VERSION 5.7 ;
  NOWIREEXTENSIONATPIN ON ;
  DIVIDERCHAR "/" ;
  BUSBITCHARS "[]" ;
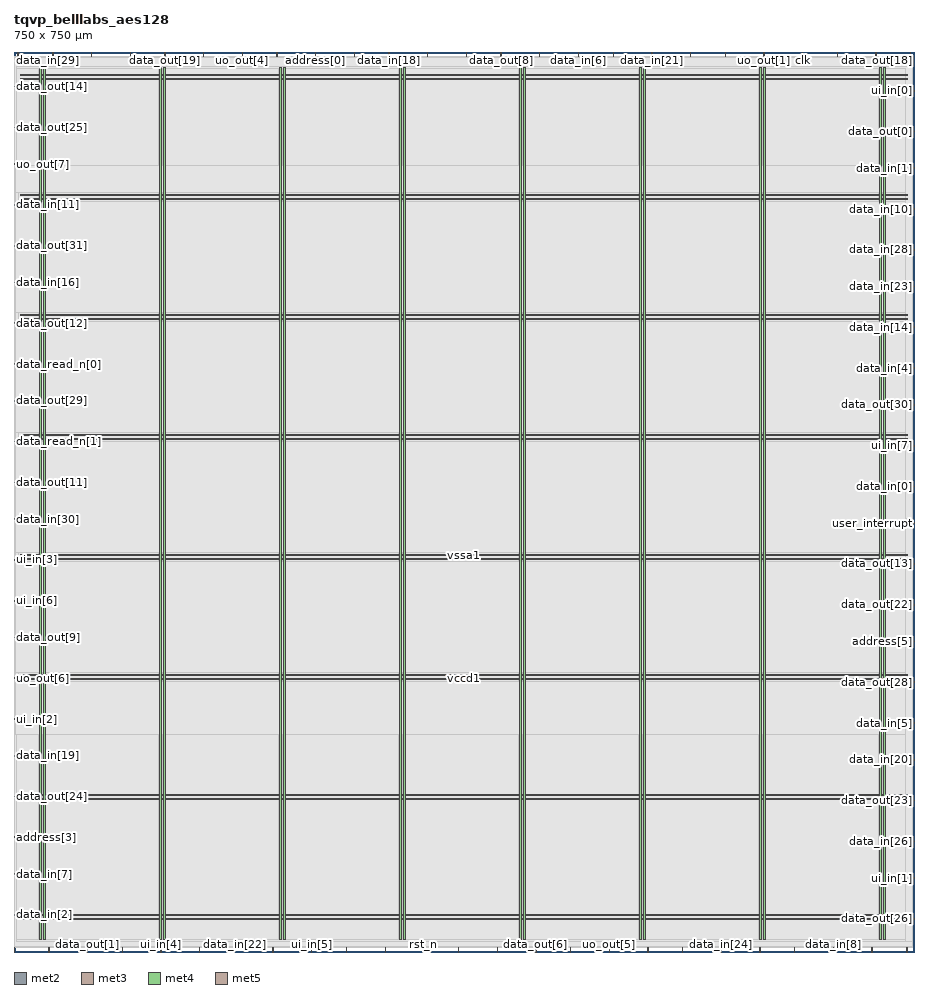
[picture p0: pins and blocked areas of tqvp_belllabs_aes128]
MACRO tqvp_belllabs_aes128
  CLASS BLOCK ;
  FOREIGN tqvp_belllabs_aes128 ;
  ORIGIN 0.000 0.000 ;
  SIZE 750.000 BY 750.000 ;
  PIN address[0]
    DIRECTION INPUT ;
    USE SIGNAL ;
    ANTENNAGATEAREA 0.647700 ;
    ANTENNADIFFAREA 0.434700 ;
    PORT
      LAYER met2 ;
        RECT 251.250 746.000 251.530 750.000 ;
    END
  END address[0]
  PIN address[1]
    DIRECTION INPUT ;
    USE SIGNAL ;
    ANTENNAGATEAREA 0.860700 ;
    ANTENNADIFFAREA 0.434700 ;
    PORT
      LAYER met2 ;
        RECT 499.190 746.000 499.470 750.000 ;
    END
  END address[1]
  PIN address[2]
    DIRECTION INPUT ;
    USE SIGNAL ;
    ANTENNAGATEAREA 0.860700 ;
    ANTENNADIFFAREA 0.434700 ;
    PORT
      LAYER met2 ;
        RECT 90.250 0.000 90.530 4.000 ;
    END
  END address[2]
  PIN address[3]
    DIRECTION INPUT ;
    USE SIGNAL ;
    ANTENNAGATEAREA 0.929700 ;
    ANTENNADIFFAREA 0.434700 ;
    PORT
      LAYER met3 ;
        RECT 0.000 95.240 4.000 95.840 ;
    END
  END address[3]
  PIN address[4]
    DIRECTION INPUT ;
    USE SIGNAL ;
    ANTENNAGATEAREA 1.177200 ;
    ANTENNADIFFAREA 0.434700 ;
    PORT
      LAYER met2 ;
        RECT 743.910 0.000 744.190 4.000 ;
    END
  END address[4]
  PIN address[5]
    DIRECTION INPUT ;
    USE SIGNAL ;
    ANTENNAGATEAREA 0.929700 ;
    ANTENNADIFFAREA 0.434700 ;
    PORT
      LAYER met3 ;
        RECT 746.000 258.440 750.000 259.040 ;
    END
  END address[5]
  PIN clk
    DIRECTION INPUT ;
    USE SIGNAL ;
    ANTENNAGATEAREA 1.286700 ;
    ANTENNADIFFAREA 0.434700 ;
    PORT
      LAYER met2 ;
        RECT 656.970 746.000 657.250 750.000 ;
    END
  END clk
  PIN data_in[0]
    DIRECTION INPUT ;
    USE SIGNAL ;
    ANTENNAGATEAREA 0.860700 ;
    ANTENNADIFFAREA 0.434700 ;
    PORT
      LAYER met3 ;
        RECT 746.000 387.640 750.000 388.240 ;
    END
  END data_in[0]
  PIN data_in[10]
    DIRECTION INPUT ;
    USE SIGNAL ;
    ANTENNAGATEAREA 1.177200 ;
    ANTENNADIFFAREA 0.434700 ;
    PORT
      LAYER met3 ;
        RECT 746.000 618.840 750.000 619.440 ;
    END
  END data_in[10]
  PIN data_in[11]
    DIRECTION INPUT ;
    USE SIGNAL ;
    ANTENNAGATEAREA 0.860700 ;
    ANTENNADIFFAREA 0.434700 ;
    PORT
      LAYER met3 ;
        RECT 0.000 622.240 4.000 622.840 ;
    END
  END data_in[11]
  PIN data_in[12]
    DIRECTION INPUT ;
    USE SIGNAL ;
    ANTENNAGATEAREA 1.177200 ;
    ANTENNADIFFAREA 0.434700 ;
    PORT
      LAYER met2 ;
        RECT 277.010 0.000 277.290 4.000 ;
    END
  END data_in[12]
  PIN data_in[13]
    DIRECTION INPUT ;
    USE SIGNAL ;
    ANTENNAGATEAREA 0.929700 ;
    ANTENNADIFFAREA 0.434700 ;
    PORT
      LAYER met2 ;
        RECT 376.830 746.000 377.110 750.000 ;
    END
  END data_in[13]
  PIN data_in[14]
    DIRECTION INPUT ;
    USE SIGNAL ;
    ANTENNAGATEAREA 1.177200 ;
    ANTENNADIFFAREA 0.434700 ;
    PORT
      LAYER met3 ;
        RECT 746.000 520.240 750.000 520.840 ;
    END
  END data_in[14]
  PIN data_in[15]
    DIRECTION INPUT ;
    USE SIGNAL ;
    ANTENNAGATEAREA 1.424700 ;
    ANTENNADIFFAREA 0.434700 ;
    PORT
      LAYER met2 ;
        RECT 714.930 0.000 715.210 4.000 ;
    END
  END data_in[15]
  PIN data_in[16]
    DIRECTION INPUT ;
    USE SIGNAL ;
    ANTENNAGATEAREA 0.631200 ;
    ANTENNADIFFAREA 0.434700 ;
    PORT
      LAYER met3 ;
        RECT 0.000 557.640 4.000 558.240 ;
    END
  END data_in[16]
  PIN data_in[17]
    DIRECTION INPUT ;
    USE SIGNAL ;
    ANTENNAGATEAREA 0.860700 ;
    ANTENNADIFFAREA 0.434700 ;
    PORT
      LAYER met2 ;
        RECT 32.290 746.000 32.570 750.000 ;
    END
  END data_in[17]
  PIN data_in[18]
    DIRECTION INPUT ;
    USE SIGNAL ;
    ANTENNAGATEAREA 0.647700 ;
    ANTENNADIFFAREA 0.434700 ;
    PORT
      LAYER met2 ;
        RECT 312.430 746.000 312.710 750.000 ;
    END
  END data_in[18]
  PIN data_in[19]
    DIRECTION INPUT ;
    USE SIGNAL ;
    ANTENNAGATEAREA 0.593700 ;
    ANTENNADIFFAREA 0.434700 ;
    PORT
      LAYER met3 ;
        RECT 0.000 163.240 4.000 163.840 ;
    END
  END data_in[19]
  PIN data_in[1]
    DIRECTION INPUT ;
    USE SIGNAL ;
    ANTENNAGATEAREA 0.682200 ;
    ANTENNADIFFAREA 0.434700 ;
    PORT
      LAYER met3 ;
        RECT 746.000 652.840 750.000 653.440 ;
    END
  END data_in[1]
  PIN data_in[20]
    DIRECTION INPUT ;
    USE SIGNAL ;
    ANTENNAGATEAREA 1.286700 ;
    ANTENNADIFFAREA 0.434700 ;
    PORT
      LAYER met3 ;
        RECT 746.000 159.840 750.000 160.440 ;
    END
  END data_in[20]
  PIN data_in[21]
    DIRECTION INPUT ;
    USE SIGNAL ;
    ANTENNAGATEAREA 0.647700 ;
    ANTENNADIFFAREA 0.434700 ;
    PORT
      LAYER met2 ;
        RECT 531.390 746.000 531.670 750.000 ;
    END
  END data_in[21]
  PIN data_in[22]
    DIRECTION INPUT ;
    USE SIGNAL ;
    ANTENNAGATEAREA 1.177200 ;
    ANTENNADIFFAREA 0.434700 ;
    PORT
      LAYER met2 ;
        RECT 183.630 0.000 183.910 4.000 ;
    END
  END data_in[22]
  PIN data_in[23]
    DIRECTION INPUT ;
    USE SIGNAL ;
    ANTENNAGATEAREA 0.682200 ;
    ANTENNADIFFAREA 0.434700 ;
    PORT
      LAYER met3 ;
        RECT 746.000 554.240 750.000 554.840 ;
    END
  END data_in[23]
  PIN data_in[24]
    DIRECTION INPUT ;
    USE SIGNAL ;
    ANTENNAGATEAREA 1.286700 ;
    ANTENNADIFFAREA 0.434700 ;
    PORT
      LAYER met2 ;
        RECT 589.350 0.000 589.630 4.000 ;
    END
  END data_in[24]
  PIN data_in[25]
    DIRECTION INPUT ;
    USE SIGNAL ;
    ANTENNAGATEAREA 0.682200 ;
    ANTENNADIFFAREA 0.434700 ;
    PORT
      LAYER met2 ;
        RECT 685.950 746.000 686.230 750.000 ;
    END
  END data_in[25]
  PIN data_in[26]
    DIRECTION INPUT ;
    USE SIGNAL ;
    ANTENNAGATEAREA 0.929700 ;
    ANTENNADIFFAREA 0.434700 ;
    PORT
      LAYER met3 ;
        RECT 746.000 91.840 750.000 92.440 ;
    END
  END data_in[26]
  PIN data_in[27]
    DIRECTION INPUT ;
    USE SIGNAL ;
    ANTENNAGATEAREA 0.647700 ;
    ANTENNADIFFAREA 0.434700 ;
    PORT
      LAYER met2 ;
        RECT 438.010 746.000 438.290 750.000 ;
    END
  END data_in[27]
  PIN data_in[28]
    DIRECTION INPUT ;
    USE SIGNAL ;
    ANTENNAGATEAREA 0.682200 ;
    ANTENNADIFFAREA 0.434700 ;
    PORT
      LAYER met3 ;
        RECT 746.000 584.840 750.000 585.440 ;
    END
  END data_in[28]
  PIN data_in[29]
    DIRECTION INPUT ;
    USE SIGNAL ;
    ANTENNAGATEAREA 0.860700 ;
    ANTENNADIFFAREA 0.434700 ;
    PORT
      LAYER met2 ;
        RECT 3.310 746.000 3.590 750.000 ;
    END
  END data_in[29]
  PIN data_in[2]
    DIRECTION INPUT ;
    USE SIGNAL ;
    ANTENNAGATEAREA 0.593700 ;
    ANTENNADIFFAREA 0.434700 ;
    PORT
      LAYER met3 ;
        RECT 0.000 30.640 4.000 31.240 ;
    END
  END data_in[2]
  PIN data_in[30]
    DIRECTION INPUT ;
    USE SIGNAL ;
    ANTENNAGATEAREA 0.631200 ;
    ANTENNADIFFAREA 0.434700 ;
    PORT
      LAYER met3 ;
        RECT 0.000 360.440 4.000 361.040 ;
    END
  END data_in[30]
  PIN data_in[31]
    DIRECTION INPUT ;
    USE SIGNAL ;
    ANTENNAGATEAREA 0.647700 ;
    ANTENNADIFFAREA 0.434700 ;
    PORT
      LAYER met2 ;
        RECT 154.650 0.000 154.930 4.000 ;
    END
  END data_in[31]
  PIN data_in[3]
    DIRECTION INPUT ;
    USE SIGNAL ;
    ANTENNAGATEAREA 0.593700 ;
    ANTENNADIFFAREA 0.434700 ;
    PORT
      LAYER met2 ;
        RECT 344.630 746.000 344.910 750.000 ;
    END
  END data_in[3]
  PIN data_in[4]
    DIRECTION INPUT ;
    USE SIGNAL ;
    ANTENNAGATEAREA 1.177200 ;
    ANTENNADIFFAREA 0.434700 ;
    PORT
      LAYER met3 ;
        RECT 746.000 486.240 750.000 486.840 ;
    END
  END data_in[4]
  PIN data_in[5]
    DIRECTION INPUT ;
    USE SIGNAL ;
    ANTENNAGATEAREA 0.682200 ;
    ANTENNADIFFAREA 0.434700 ;
    PORT
      LAYER met3 ;
        RECT 746.000 190.440 750.000 191.040 ;
    END
  END data_in[5]
  PIN data_in[6]
    DIRECTION INPUT ;
    USE SIGNAL ;
    ANTENNAGATEAREA 0.593700 ;
    ANTENNADIFFAREA 0.434700 ;
    PORT
      LAYER met2 ;
        RECT 470.210 746.000 470.490 750.000 ;
    END
  END data_in[6]
  PIN data_in[7]
    DIRECTION INPUT ;
    USE SIGNAL ;
    ANTENNAGATEAREA 0.647700 ;
    ANTENNADIFFAREA 0.434700 ;
    PORT
      LAYER met3 ;
        RECT 0.000 64.640 4.000 65.240 ;
    END
  END data_in[7]
  PIN data_in[8]
    DIRECTION INPUT ;
    USE SIGNAL ;
    ANTENNAGATEAREA 1.286700 ;
    ANTENNADIFFAREA 0.434700 ;
    PORT
      LAYER met2 ;
        RECT 682.730 0.000 683.010 4.000 ;
    END
  END data_in[8]
  PIN data_in[9]
    DIRECTION INPUT ;
    USE SIGNAL ;
    ANTENNAGATEAREA 0.860700 ;
    ANTENNADIFFAREA 0.434700 ;
    PORT
      LAYER met2 ;
        RECT 283.450 746.000 283.730 750.000 ;
    END
  END data_in[9]
  PIN data_out[0]
    DIRECTION OUTPUT TRISTATE ;
    USE SIGNAL ;
    ANTENNADIFFAREA 0.445500 ;
    PORT
      LAYER met3 ;
        RECT 746.000 683.440 750.000 684.040 ;
    END
  END data_out[0]
  PIN data_out[10]
    DIRECTION OUTPUT TRISTATE ;
    USE SIGNAL ;
    ANTENNADIFFAREA 0.795200 ;
    PORT
      LAYER met2 ;
        RECT 463.770 0.000 464.050 4.000 ;
    END
  END data_out[10]
  PIN data_out[11]
    DIRECTION OUTPUT TRISTATE ;
    USE SIGNAL ;
    ANTENNADIFFAREA 0.795200 ;
    PORT
      LAYER met3 ;
        RECT 0.000 391.040 4.000 391.640 ;
    END
  END data_out[11]
  PIN data_out[12]
    DIRECTION OUTPUT TRISTATE ;
    USE SIGNAL ;
    ANTENNADIFFAREA 0.795200 ;
    PORT
      LAYER met3 ;
        RECT 0.000 523.640 4.000 524.240 ;
    END
  END data_out[12]
  PIN data_out[13]
    DIRECTION OUTPUT TRISTATE ;
    USE SIGNAL ;
    ANTENNADIFFAREA 0.445500 ;
    PORT
      LAYER met3 ;
        RECT 746.000 323.040 750.000 323.640 ;
    END
  END data_out[13]
  PIN data_out[14]
    DIRECTION OUTPUT TRISTATE ;
    USE SIGNAL ;
    ANTENNADIFFAREA 0.795200 ;
    PORT
      LAYER met3 ;
        RECT 0.000 720.840 4.000 721.440 ;
    END
  END data_out[14]
  PIN data_out[15]
    DIRECTION OUTPUT TRISTATE ;
    USE SIGNAL ;
    ANTENNADIFFAREA 0.795200 ;
    PORT
      LAYER met2 ;
        RECT 621.550 0.000 621.830 4.000 ;
    END
  END data_out[15]
  PIN data_out[16]
    DIRECTION OUTPUT TRISTATE ;
    USE SIGNAL ;
    ANTENNADIFFAREA 0.795200 ;
    PORT
      LAYER met2 ;
        RECT 309.210 0.000 309.490 4.000 ;
    END
  END data_out[16]
  PIN data_out[17]
    DIRECTION OUTPUT TRISTATE ;
    USE SIGNAL ;
    ANTENNADIFFAREA 0.795200 ;
    PORT
      LAYER met2 ;
        RECT 528.170 0.000 528.450 4.000 ;
    END
  END data_out[17]
  PIN data_out[18]
    DIRECTION OUTPUT TRISTATE ;
    USE SIGNAL ;
    ANTENNADIFFAREA 0.795200 ;
    PORT
      LAYER met2 ;
        RECT 747.130 746.000 747.410 750.000 ;
    END
  END data_out[18]
  PIN data_out[19]
    DIRECTION OUTPUT TRISTATE ;
    USE SIGNAL ;
    ANTENNADIFFAREA 0.795200 ;
    PORT
      LAYER met2 ;
        RECT 125.670 746.000 125.950 750.000 ;
    END
  END data_out[19]
  PIN data_out[1]
    DIRECTION OUTPUT TRISTATE ;
    USE SIGNAL ;
    ANTENNADIFFAREA 0.795200 ;
    PORT
      LAYER met2 ;
        RECT 61.270 0.000 61.550 4.000 ;
    END
  END data_out[1]
  PIN data_out[20]
    DIRECTION OUTPUT TRISTATE ;
    USE SIGNAL ;
    ANTENNADIFFAREA 0.795200 ;
    PORT
      LAYER met2 ;
        RECT 215.830 0.000 216.110 4.000 ;
    END
  END data_out[20]
  PIN data_out[21]
    DIRECTION OUTPUT TRISTATE ;
    USE SIGNAL ;
    ANTENNADIFFAREA 0.795200 ;
    PORT
      LAYER met2 ;
        RECT 650.530 0.000 650.810 4.000 ;
    END
  END data_out[21]
  PIN data_out[22]
    DIRECTION OUTPUT TRISTATE ;
    USE SIGNAL ;
    ANTENNADIFFAREA 0.445500 ;
    PORT
      LAYER met3 ;
        RECT 746.000 289.040 750.000 289.640 ;
    END
  END data_out[22]
  PIN data_out[23]
    DIRECTION OUTPUT TRISTATE ;
    USE SIGNAL ;
    ANTENNADIFFAREA 0.445500 ;
    PORT
      LAYER met3 ;
        RECT 746.000 125.840 750.000 126.440 ;
    END
  END data_out[23]
  PIN data_out[24]
    DIRECTION OUTPUT TRISTATE ;
    USE SIGNAL ;
    ANTENNADIFFAREA 0.795200 ;
    PORT
      LAYER met3 ;
        RECT 0.000 129.240 4.000 129.840 ;
    END
  END data_out[24]
  PIN data_out[25]
    DIRECTION OUTPUT TRISTATE ;
    USE SIGNAL ;
    ANTENNADIFFAREA 0.795200 ;
    PORT
      LAYER met3 ;
        RECT 0.000 686.840 4.000 687.440 ;
    END
  END data_out[25]
  PIN data_out[26]
    DIRECTION OUTPUT TRISTATE ;
    USE SIGNAL ;
    ANTENNADIFFAREA 0.795200 ;
    PORT
      LAYER met3 ;
        RECT 746.000 27.240 750.000 27.840 ;
    END
  END data_out[26]
  PIN data_out[27]
    DIRECTION OUTPUT TRISTATE ;
    USE SIGNAL ;
    ANTENNADIFFAREA 0.795200 ;
    PORT
      LAYER met2 ;
        RECT 157.870 746.000 158.150 750.000 ;
    END
  END data_out[27]
  PIN data_out[28]
    DIRECTION OUTPUT TRISTATE ;
    USE SIGNAL ;
    ANTENNADIFFAREA 0.445500 ;
    PORT
      LAYER met3 ;
        RECT 746.000 224.440 750.000 225.040 ;
    END
  END data_out[28]
  PIN data_out[29]
    DIRECTION OUTPUT TRISTATE ;
    USE SIGNAL ;
    ANTENNADIFFAREA 0.795200 ;
    PORT
      LAYER met3 ;
        RECT 0.000 459.040 4.000 459.640 ;
    END
  END data_out[29]
  PIN data_out[2]
    DIRECTION OUTPUT TRISTATE ;
    USE SIGNAL ;
    ANTENNADIFFAREA 0.795200 ;
    PORT
      LAYER met2 ;
        RECT 557.150 0.000 557.430 4.000 ;
    END
  END data_out[2]
  PIN data_out[30]
    DIRECTION OUTPUT TRISTATE ;
    USE SIGNAL ;
    ANTENNADIFFAREA 0.445500 ;
    PORT
      LAYER met3 ;
        RECT 746.000 455.640 750.000 456.240 ;
    END
  END data_out[30]
  PIN data_out[31]
    DIRECTION OUTPUT TRISTATE ;
    USE SIGNAL ;
    ANTENNADIFFAREA 0.795200 ;
    PORT
      LAYER met3 ;
        RECT 0.000 588.240 4.000 588.840 ;
    END
  END data_out[31]
  PIN data_out[3]
    DIRECTION OUTPUT TRISTATE ;
    USE SIGNAL ;
    ANTENNADIFFAREA 0.795200 ;
    PORT
      LAYER met2 ;
        RECT 96.690 746.000 96.970 750.000 ;
    END
  END data_out[3]
  PIN data_out[4]
    DIRECTION OUTPUT TRISTATE ;
    USE SIGNAL ;
    ANTENNADIFFAREA 0.795200 ;
    PORT
      LAYER met2 ;
        RECT 370.390 0.000 370.670 4.000 ;
    END
  END data_out[4]
  PIN data_out[5]
    DIRECTION OUTPUT TRISTATE ;
    USE SIGNAL ;
    ANTENNADIFFAREA 0.795200 ;
    PORT
      LAYER met2 ;
        RECT 0.090 0.000 0.370 4.000 ;
    END
  END data_out[5]
  PIN data_out[6]
    DIRECTION OUTPUT TRISTATE ;
    USE SIGNAL ;
    ANTENNADIFFAREA 0.795200 ;
    PORT
      LAYER met2 ;
        RECT 434.790 0.000 435.070 4.000 ;
    END
  END data_out[6]
  PIN data_out[7]
    DIRECTION OUTPUT TRISTATE ;
    USE SIGNAL ;
    ANTENNADIFFAREA 0.795200 ;
    PORT
      LAYER met2 ;
        RECT 219.050 746.000 219.330 750.000 ;
    END
  END data_out[7]
  PIN data_out[8]
    DIRECTION OUTPUT TRISTATE ;
    USE SIGNAL ;
    ANTENNADIFFAREA 0.795200 ;
    PORT
      LAYER met2 ;
        RECT 405.810 746.000 406.090 750.000 ;
    END
  END data_out[8]
  PIN data_out[9]
    DIRECTION OUTPUT TRISTATE ;
    USE SIGNAL ;
    ANTENNADIFFAREA 0.795200 ;
    PORT
      LAYER met3 ;
        RECT 0.000 261.840 4.000 262.440 ;
    END
  END data_out[9]
  PIN data_read_n[0]
    DIRECTION INPUT ;
    USE SIGNAL ;
    PORT
      LAYER met3 ;
        RECT 0.000 489.640 4.000 490.240 ;
    END
  END data_read_n[0]
  PIN data_read_n[1]
    DIRECTION INPUT ;
    USE SIGNAL ;
    PORT
      LAYER met3 ;
        RECT 0.000 425.040 4.000 425.640 ;
    END
  END data_read_n[1]
  PIN data_ready
    DIRECTION OUTPUT TRISTATE ;
    USE SIGNAL ;
    PORT
      LAYER met2 ;
        RECT 29.070 0.000 29.350 4.000 ;
    END
  END data_ready
  PIN data_write_n[0]
    DIRECTION INPUT ;
    USE SIGNAL ;
    ANTENNAGATEAREA 0.860700 ;
    ANTENNADIFFAREA 0.434700 ;
    PORT
      LAYER met2 ;
        RECT 718.150 746.000 718.430 750.000 ;
    END
  END data_write_n[0]
  PIN data_write_n[1]
    DIRECTION INPUT ;
    USE SIGNAL ;
    ANTENNAGATEAREA 0.682200 ;
    ANTENNADIFFAREA 0.434700 ;
    PORT
      LAYER met2 ;
        RECT 563.590 746.000 563.870 750.000 ;
    END
  END data_write_n[1]
  PIN rst_n
    DIRECTION INPUT ;
    USE SIGNAL ;
    ANTENNAGATEAREA 0.647700 ;
    ANTENNADIFFAREA 0.434700 ;
    PORT
      LAYER met2 ;
        RECT 341.410 0.000 341.690 4.000 ;
    END
  END rst_n
  PIN ui_in[0]
    DIRECTION INPUT ;
    USE SIGNAL ;
    PORT
      LAYER met3 ;
        RECT 746.000 717.440 750.000 718.040 ;
    END
  END ui_in[0]
  PIN ui_in[1]
    DIRECTION INPUT ;
    USE SIGNAL ;
    PORT
      LAYER met3 ;
        RECT 746.000 61.240 750.000 61.840 ;
    END
  END ui_in[1]
  PIN ui_in[2]
    DIRECTION INPUT ;
    USE SIGNAL ;
    PORT
      LAYER met3 ;
        RECT 0.000 193.840 4.000 194.440 ;
    END
  END ui_in[2]
  PIN ui_in[3]
    DIRECTION INPUT ;
    USE SIGNAL ;
    PORT
      LAYER met3 ;
        RECT 0.000 326.440 4.000 327.040 ;
    END
  END ui_in[3]
  PIN ui_in[4]
    DIRECTION INPUT ;
    USE SIGNAL ;
    PORT
      LAYER met2 ;
        RECT 122.450 0.000 122.730 4.000 ;
    END
  END ui_in[4]
  PIN ui_in[5]
    DIRECTION INPUT ;
    USE SIGNAL ;
    PORT
      LAYER met2 ;
        RECT 248.030 0.000 248.310 4.000 ;
    END
  END ui_in[5]
  PIN ui_in[6]
    DIRECTION INPUT ;
    USE SIGNAL ;
    PORT
      LAYER met3 ;
        RECT 0.000 292.440 4.000 293.040 ;
    END
  END ui_in[6]
  PIN ui_in[7]
    DIRECTION INPUT ;
    USE SIGNAL ;
    PORT
      LAYER met3 ;
        RECT 746.000 421.640 750.000 422.240 ;
    END
  END ui_in[7]
  PIN uo_out[0]
    DIRECTION OUTPUT TRISTATE ;
    USE SIGNAL ;
    PORT
      LAYER met2 ;
        RECT 402.590 0.000 402.870 4.000 ;
    END
  END uo_out[0]
  PIN uo_out[1]
    DIRECTION OUTPUT TRISTATE ;
    USE SIGNAL ;
    PORT
      LAYER met2 ;
        RECT 624.770 746.000 625.050 750.000 ;
    END
  END uo_out[1]
  PIN uo_out[2]
    DIRECTION OUTPUT TRISTATE ;
    USE SIGNAL ;
    PORT
      LAYER met2 ;
        RECT 592.570 746.000 592.850 750.000 ;
    END
  END uo_out[2]
  PIN uo_out[3]
    DIRECTION OUTPUT TRISTATE ;
    USE SIGNAL ;
    PORT
      LAYER met2 ;
        RECT 64.490 746.000 64.770 750.000 ;
    END
  END uo_out[3]
  PIN uo_out[4]
    DIRECTION OUTPUT TRISTATE ;
    USE SIGNAL ;
    PORT
      LAYER met2 ;
        RECT 190.070 746.000 190.350 750.000 ;
    END
  END uo_out[4]
  PIN uo_out[5]
    DIRECTION OUTPUT TRISTATE ;
    USE SIGNAL ;
    PORT
      LAYER met2 ;
        RECT 495.970 0.000 496.250 4.000 ;
    END
  END uo_out[5]
  PIN uo_out[6]
    DIRECTION OUTPUT TRISTATE ;
    USE SIGNAL ;
    PORT
      LAYER met3 ;
        RECT 0.000 227.840 4.000 228.440 ;
    END
  END uo_out[6]
  PIN uo_out[7]
    DIRECTION OUTPUT TRISTATE ;
    USE SIGNAL ;
    PORT
      LAYER met3 ;
        RECT 0.000 656.240 4.000 656.840 ;
    END
  END uo_out[7]
  PIN user_interrupt
    DIRECTION OUTPUT TRISTATE ;
    USE SIGNAL ;
    ANTENNADIFFAREA 0.795200 ;
    PORT
      LAYER met3 ;
        RECT 746.000 357.040 750.000 357.640 ;
    END
  END user_interrupt
  PIN vccd1
    DIRECTION INOUT ;
    USE POWER ;
    PORT
      LAYER met4 ;
        RECT 21.040 10.640 22.640 737.360 ;
    END
    PORT
      LAYER met4 ;
        RECT 121.040 10.640 122.640 737.360 ;
    END
    PORT
      LAYER met4 ;
        RECT 221.040 10.640 222.640 737.360 ;
    END
    PORT
      LAYER met4 ;
        RECT 321.040 10.640 322.640 737.360 ;
    END
    PORT
      LAYER met4 ;
        RECT 421.040 10.640 422.640 737.360 ;
    END
    PORT
      LAYER met4 ;
        RECT 521.040 10.640 522.640 737.360 ;
    END
    PORT
      LAYER met4 ;
        RECT 621.040 10.640 622.640 737.360 ;
    END
    PORT
      LAYER met4 ;
        RECT 721.040 10.640 722.640 737.360 ;
    END
    PORT
      LAYER met5 ;
        RECT 5.280 26.730 744.520 28.330 ;
    END
    PORT
      LAYER met5 ;
        RECT 5.280 126.730 744.520 128.330 ;
    END
    PORT
      LAYER met5 ;
        RECT 5.280 226.730 744.520 228.330 ;
    END
    PORT
      LAYER met5 ;
        RECT 5.280 326.730 744.520 328.330 ;
    END
    PORT
      LAYER met5 ;
        RECT 5.280 426.730 744.520 428.330 ;
    END
    PORT
      LAYER met5 ;
        RECT 5.280 526.730 744.520 528.330 ;
    END
    PORT
      LAYER met5 ;
        RECT 5.280 626.730 744.520 628.330 ;
    END
    PORT
      LAYER met5 ;
        RECT 5.280 726.730 744.520 728.330 ;
    END
  END vccd1
  PIN vssa1
    DIRECTION INOUT ;
    USE GROUND ;
    PORT
      LAYER met4 ;
        RECT 24.340 10.640 25.940 737.360 ;
    END
    PORT
      LAYER met4 ;
        RECT 124.340 10.640 125.940 737.360 ;
    END
    PORT
      LAYER met4 ;
        RECT 224.340 10.640 225.940 737.360 ;
    END
    PORT
      LAYER met4 ;
        RECT 324.340 10.640 325.940 737.360 ;
    END
    PORT
      LAYER met4 ;
        RECT 424.340 10.640 425.940 737.360 ;
    END
    PORT
      LAYER met4 ;
        RECT 524.340 10.640 525.940 737.360 ;
    END
    PORT
      LAYER met4 ;
        RECT 624.340 10.640 625.940 737.360 ;
    END
    PORT
      LAYER met4 ;
        RECT 724.340 10.640 725.940 737.360 ;
    END
    PORT
      LAYER met5 ;
        RECT 5.280 30.030 744.520 31.630 ;
    END
    PORT
      LAYER met5 ;
        RECT 5.280 130.030 744.520 131.630 ;
    END
    PORT
      LAYER met5 ;
        RECT 5.280 230.030 744.520 231.630 ;
    END
    PORT
      LAYER met5 ;
        RECT 5.280 330.030 744.520 331.630 ;
    END
    PORT
      LAYER met5 ;
        RECT 5.280 430.030 744.520 431.630 ;
    END
    PORT
      LAYER met5 ;
        RECT 5.280 530.030 744.520 531.630 ;
    END
    PORT
      LAYER met5 ;
        RECT 5.280 630.030 744.520 631.630 ;
    END
    PORT
      LAYER met5 ;
        RECT 5.280 730.030 744.520 731.630 ;
    END
  END vssa1
  OBS
      LAYER li1 ;
        RECT 5.520 10.795 744.280 737.205 ;
      LAYER met1 ;
        RECT 0.070 10.240 748.810 738.100 ;
      LAYER met2 ;
        RECT 0.100 745.720 3.030 746.000 ;
        RECT 3.870 745.720 32.010 746.000 ;
        RECT 32.850 745.720 64.210 746.000 ;
        RECT 65.050 745.720 96.410 746.000 ;
        RECT 97.250 745.720 125.390 746.000 ;
        RECT 126.230 745.720 157.590 746.000 ;
        RECT 158.430 745.720 189.790 746.000 ;
        RECT 190.630 745.720 218.770 746.000 ;
        RECT 219.610 745.720 250.970 746.000 ;
        RECT 251.810 745.720 283.170 746.000 ;
        RECT 284.010 745.720 312.150 746.000 ;
        RECT 312.990 745.720 344.350 746.000 ;
        RECT 345.190 745.720 376.550 746.000 ;
        RECT 377.390 745.720 405.530 746.000 ;
        RECT 406.370 745.720 437.730 746.000 ;
        RECT 438.570 745.720 469.930 746.000 ;
        RECT 470.770 745.720 498.910 746.000 ;
        RECT 499.750 745.720 531.110 746.000 ;
        RECT 531.950 745.720 563.310 746.000 ;
        RECT 564.150 745.720 592.290 746.000 ;
        RECT 593.130 745.720 624.490 746.000 ;
        RECT 625.330 745.720 656.690 746.000 ;
        RECT 657.530 745.720 685.670 746.000 ;
        RECT 686.510 745.720 717.870 746.000 ;
        RECT 718.710 745.720 746.850 746.000 ;
        RECT 747.690 745.720 748.790 746.000 ;
        RECT 0.100 4.280 748.790 745.720 ;
        RECT 0.650 3.670 28.790 4.280 ;
        RECT 29.630 3.670 60.990 4.280 ;
        RECT 61.830 3.670 89.970 4.280 ;
        RECT 90.810 3.670 122.170 4.280 ;
        RECT 123.010 3.670 154.370 4.280 ;
        RECT 155.210 3.670 183.350 4.280 ;
        RECT 184.190 3.670 215.550 4.280 ;
        RECT 216.390 3.670 247.750 4.280 ;
        RECT 248.590 3.670 276.730 4.280 ;
        RECT 277.570 3.670 308.930 4.280 ;
        RECT 309.770 3.670 341.130 4.280 ;
        RECT 341.970 3.670 370.110 4.280 ;
        RECT 370.950 3.670 402.310 4.280 ;
        RECT 403.150 3.670 434.510 4.280 ;
        RECT 435.350 3.670 463.490 4.280 ;
        RECT 464.330 3.670 495.690 4.280 ;
        RECT 496.530 3.670 527.890 4.280 ;
        RECT 528.730 3.670 556.870 4.280 ;
        RECT 557.710 3.670 589.070 4.280 ;
        RECT 589.910 3.670 621.270 4.280 ;
        RECT 622.110 3.670 650.250 4.280 ;
        RECT 651.090 3.670 682.450 4.280 ;
        RECT 683.290 3.670 714.650 4.280 ;
        RECT 715.490 3.670 743.630 4.280 ;
        RECT 744.470 3.670 748.790 4.280 ;
      LAYER met3 ;
        RECT 2.110 721.840 748.815 738.305 ;
        RECT 4.400 720.440 748.815 721.840 ;
        RECT 2.110 718.440 748.815 720.440 ;
        RECT 2.110 717.040 745.600 718.440 ;
        RECT 2.110 687.840 748.815 717.040 ;
        RECT 4.400 686.440 748.815 687.840 ;
        RECT 2.110 684.440 748.815 686.440 ;
        RECT 2.110 683.040 745.600 684.440 ;
        RECT 2.110 657.240 748.815 683.040 ;
        RECT 4.400 655.840 748.815 657.240 ;
        RECT 2.110 653.840 748.815 655.840 ;
        RECT 2.110 652.440 745.600 653.840 ;
        RECT 2.110 623.240 748.815 652.440 ;
        RECT 4.400 621.840 748.815 623.240 ;
        RECT 2.110 619.840 748.815 621.840 ;
        RECT 2.110 618.440 745.600 619.840 ;
        RECT 2.110 589.240 748.815 618.440 ;
        RECT 4.400 587.840 748.815 589.240 ;
        RECT 2.110 585.840 748.815 587.840 ;
        RECT 2.110 584.440 745.600 585.840 ;
        RECT 2.110 558.640 748.815 584.440 ;
        RECT 4.400 557.240 748.815 558.640 ;
        RECT 2.110 555.240 748.815 557.240 ;
        RECT 2.110 553.840 745.600 555.240 ;
        RECT 2.110 524.640 748.815 553.840 ;
        RECT 4.400 523.240 748.815 524.640 ;
        RECT 2.110 521.240 748.815 523.240 ;
        RECT 2.110 519.840 745.600 521.240 ;
        RECT 2.110 490.640 748.815 519.840 ;
        RECT 4.400 489.240 748.815 490.640 ;
        RECT 2.110 487.240 748.815 489.240 ;
        RECT 2.110 485.840 745.600 487.240 ;
        RECT 2.110 460.040 748.815 485.840 ;
        RECT 4.400 458.640 748.815 460.040 ;
        RECT 2.110 456.640 748.815 458.640 ;
        RECT 2.110 455.240 745.600 456.640 ;
        RECT 2.110 426.040 748.815 455.240 ;
        RECT 4.400 424.640 748.815 426.040 ;
        RECT 2.110 422.640 748.815 424.640 ;
        RECT 2.110 421.240 745.600 422.640 ;
        RECT 2.110 392.040 748.815 421.240 ;
        RECT 4.400 390.640 748.815 392.040 ;
        RECT 2.110 388.640 748.815 390.640 ;
        RECT 2.110 387.240 745.600 388.640 ;
        RECT 2.110 361.440 748.815 387.240 ;
        RECT 4.400 360.040 748.815 361.440 ;
        RECT 2.110 358.040 748.815 360.040 ;
        RECT 2.110 356.640 745.600 358.040 ;
        RECT 2.110 327.440 748.815 356.640 ;
        RECT 4.400 326.040 748.815 327.440 ;
        RECT 2.110 324.040 748.815 326.040 ;
        RECT 2.110 322.640 745.600 324.040 ;
        RECT 2.110 293.440 748.815 322.640 ;
        RECT 4.400 292.040 748.815 293.440 ;
        RECT 2.110 290.040 748.815 292.040 ;
        RECT 2.110 288.640 745.600 290.040 ;
        RECT 2.110 262.840 748.815 288.640 ;
        RECT 4.400 261.440 748.815 262.840 ;
        RECT 2.110 259.440 748.815 261.440 ;
        RECT 2.110 258.040 745.600 259.440 ;
        RECT 2.110 228.840 748.815 258.040 ;
        RECT 4.400 227.440 748.815 228.840 ;
        RECT 2.110 225.440 748.815 227.440 ;
        RECT 2.110 224.040 745.600 225.440 ;
        RECT 2.110 194.840 748.815 224.040 ;
        RECT 4.400 193.440 748.815 194.840 ;
        RECT 2.110 191.440 748.815 193.440 ;
        RECT 2.110 190.040 745.600 191.440 ;
        RECT 2.110 164.240 748.815 190.040 ;
        RECT 4.400 162.840 748.815 164.240 ;
        RECT 2.110 160.840 748.815 162.840 ;
        RECT 2.110 159.440 745.600 160.840 ;
        RECT 2.110 130.240 748.815 159.440 ;
        RECT 4.400 128.840 748.815 130.240 ;
        RECT 2.110 126.840 748.815 128.840 ;
        RECT 2.110 125.440 745.600 126.840 ;
        RECT 2.110 96.240 748.815 125.440 ;
        RECT 4.400 94.840 748.815 96.240 ;
        RECT 2.110 92.840 748.815 94.840 ;
        RECT 2.110 91.440 745.600 92.840 ;
        RECT 2.110 65.640 748.815 91.440 ;
        RECT 4.400 64.240 748.815 65.640 ;
        RECT 2.110 62.240 748.815 64.240 ;
        RECT 2.110 60.840 745.600 62.240 ;
        RECT 2.110 31.640 748.815 60.840 ;
        RECT 4.400 30.240 748.815 31.640 ;
        RECT 2.110 28.240 748.815 30.240 ;
        RECT 2.110 26.840 745.600 28.240 ;
        RECT 2.110 9.015 748.815 26.840 ;
      LAYER met4 ;
        RECT 1.710 10.240 20.640 736.265 ;
        RECT 23.040 10.240 23.940 736.265 ;
        RECT 26.340 10.240 120.640 736.265 ;
        RECT 123.040 10.240 123.940 736.265 ;
        RECT 126.340 10.240 220.640 736.265 ;
        RECT 223.040 10.240 223.940 736.265 ;
        RECT 226.340 10.240 320.640 736.265 ;
        RECT 323.040 10.240 323.940 736.265 ;
        RECT 326.340 10.240 420.640 736.265 ;
        RECT 423.040 10.240 423.940 736.265 ;
        RECT 426.340 10.240 520.640 736.265 ;
        RECT 523.040 10.240 523.940 736.265 ;
        RECT 526.340 10.240 620.640 736.265 ;
        RECT 623.040 10.240 623.940 736.265 ;
        RECT 626.340 10.240 720.640 736.265 ;
        RECT 723.040 10.240 723.940 736.265 ;
        RECT 726.340 10.240 742.570 736.265 ;
        RECT 1.710 9.015 742.570 10.240 ;
      LAYER met5 ;
        RECT 1.500 633.230 742.780 655.300 ;
        RECT 1.500 625.130 3.680 633.230 ;
        RECT 1.500 533.230 742.780 625.130 ;
        RECT 1.500 525.130 3.680 533.230 ;
        RECT 1.500 433.230 742.780 525.130 ;
        RECT 1.500 425.130 3.680 433.230 ;
        RECT 1.500 333.230 742.780 425.130 ;
        RECT 1.500 325.130 3.680 333.230 ;
        RECT 1.500 233.230 742.780 325.130 ;
        RECT 1.500 225.130 3.680 233.230 ;
        RECT 1.500 181.100 742.780 225.130 ;
  END
END tqvp_belllabs_aes128
END LIBRARY

